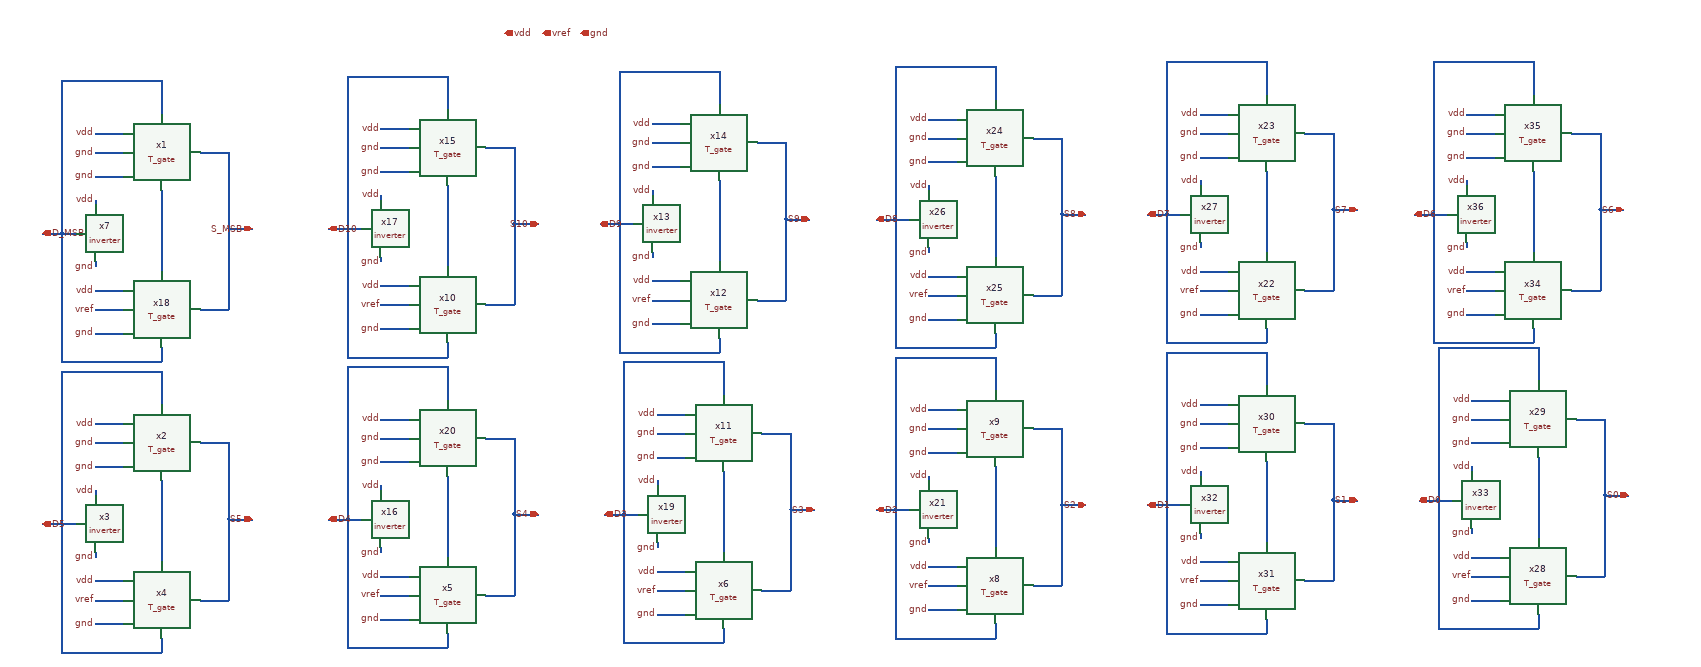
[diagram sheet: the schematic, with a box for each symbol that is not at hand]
v {xschem version=3.4.8RC file_version=1.3}
G {}
K {}
V {}
S {}
F {}
E {}
N 440 -690 440 -660 {lab=D_MSB}
N 520 -770 580 -770 {lab=S_MSB}
N 440 -1020 440 -850 {lab=#net1}
N 520 -1100 580 -1100 {lab=S_MSB}
N 580 -940 580 -770 {lab=S_MSB}
N 580 -1100 580 -940 {lab=S_MSB}
N 440 -1250 440 -1180 {lab=D_MSB}
N 230 -1250 440 -1250 {lab=D_MSB}
N 230 -1250 230 -930 {lab=D_MSB}
N 230 -930 260 -930 {lab=D_MSB}
N 300 -770 360 -770 {lab=vref}
N 300 -720 360 -720 {lab=gnd}
N 300 -810 360 -810 {lab=vdd}
N 230 -930 230 -660 {lab=D_MSB}
N 230 -660 440 -660 {lab=D_MSB}
N 300 -1100 360 -1100 {lab=gnd}
N 300 -1050 360 -1050 {lab=gnd}
N 300 -1140 360 -1140 {lab=vdd}
N 190 -930 230 -930 {lab=D_MSB}
N 300 -1000 300 -990 {lab=vdd}
N 300 -870 300 -860 {lab=gnd}
N 580 -940 630 -940 {lab=S_MSB}
N 1610 -710 1610 -680 {lab=D9}
N 1690 -790 1750 -790 {lab=S9}
N 1610 -1040 1610 -870 {lab=#net2}
N 1690 -1120 1750 -1120 {lab=S9}
N 1750 -960 1750 -790 {lab=S9}
N 1750 -1120 1750 -960 {lab=S9}
N 1610 -1270 1610 -1200 {lab=D9}
N 1400 -1270 1610 -1270 {lab=D9}
N 1400 -1270 1400 -950 {lab=D9}
N 1400 -950 1430 -950 {lab=D9}
N 1470 -790 1530 -790 {lab=vref}
N 1470 -740 1530 -740 {lab=gnd}
N 1470 -830 1530 -830 {lab=vdd}
N 1400 -950 1400 -680 {lab=D9}
N 1400 -680 1610 -680 {lab=D9}
N 1470 -1120 1530 -1120 {lab=gnd}
N 1470 -1070 1530 -1070 {lab=gnd}
N 1470 -1160 1530 -1160 {lab=vdd}
N 1360 -950 1400 -950 {lab=D9}
N 1470 -1020 1470 -1010 {lab=vdd}
N 1470 -890 1470 -880 {lab=gnd}
N 1750 -960 1800 -960 {lab=S9}
N 440 -80 440 -50 {lab=D5}
N 520 -160 580 -160 {lab=S5}
N 440 -410 440 -240 {lab=#net3}
N 520 -490 580 -490 {lab=S5}
N 580 -330 580 -160 {lab=S5}
N 580 -490 580 -330 {lab=S5}
N 440 -640 440 -570 {lab=D5}
N 230 -640 440 -640 {lab=D5}
N 230 -640 230 -320 {lab=D5}
N 230 -320 260 -320 {lab=D5}
N 300 -160 360 -160 {lab=vref}
N 300 -110 360 -110 {lab=gnd}
N 300 -200 360 -200 {lab=vdd}
N 230 -320 230 -50 {lab=D5}
N 230 -50 440 -50 {lab=D5}
N 300 -490 360 -490 {lab=gnd}
N 300 -440 360 -440 {lab=gnd}
N 300 -530 360 -530 {lab=vdd}
N 190 -320 230 -320 {lab=D5}
N 300 -390 300 -380 {lab=vdd}
N 300 -260 300 -250 {lab=gnd}
N 580 -330 630 -330 {lab=S5}
N 1040 -90 1040 -60 {lab=D4}
N 1120 -170 1180 -170 {lab=S4}
N 1040 -420 1040 -250 {lab=#net4}
N 1120 -500 1180 -500 {lab=S4}
N 1180 -340 1180 -170 {lab=S4}
N 1180 -500 1180 -340 {lab=S4}
N 1040 -650 1040 -580 {lab=D4}
N 830 -650 1040 -650 {lab=D4}
N 830 -650 830 -330 {lab=D4}
N 830 -330 860 -330 {lab=D4}
N 900 -170 960 -170 {lab=vref}
N 900 -120 960 -120 {lab=gnd}
N 900 -210 960 -210 {lab=vdd}
N 830 -330 830 -60 {lab=D4}
N 830 -60 1040 -60 {lab=D4}
N 900 -500 960 -500 {lab=gnd}
N 900 -450 960 -450 {lab=gnd}
N 900 -540 960 -540 {lab=vdd}
N 790 -330 830 -330 {lab=D4}
N 900 -400 900 -390 {lab=vdd}
N 900 -270 900 -260 {lab=gnd}
N 1180 -340 1230 -340 {lab=S4}
N 1620 -100 1620 -70 {lab=D3}
N 1700 -180 1760 -180 {lab=S3}
N 1620 -430 1620 -260 {lab=#net5}
N 1700 -510 1760 -510 {lab=S3}
N 1760 -350 1760 -180 {lab=S3}
N 1760 -510 1760 -350 {lab=S3}
N 1620 -660 1620 -590 {lab=D3}
N 1410 -660 1620 -660 {lab=D3}
N 1410 -660 1410 -340 {lab=D3}
N 1410 -340 1440 -340 {lab=D3}
N 1480 -180 1540 -180 {lab=vref}
N 1480 -130 1540 -130 {lab=gnd}
N 1480 -220 1540 -220 {lab=vdd}
N 1410 -340 1410 -70 {lab=D3}
N 1410 -70 1620 -70 {lab=D3}
N 1480 -510 1540 -510 {lab=gnd}
N 1480 -460 1540 -460 {lab=gnd}
N 1480 -550 1540 -550 {lab=vdd}
N 1370 -340 1410 -340 {lab=D3}
N 1480 -410 1480 -400 {lab=vdd}
N 1480 -280 1480 -270 {lab=gnd}
N 1760 -350 1810 -350 {lab=S3}
N 2190 -110 2190 -80 {lab=D2}
N 2270 -190 2330 -190 {lab=S2}
N 2190 -440 2190 -270 {lab=#net6}
N 2270 -520 2330 -520 {lab=S2}
N 2330 -360 2330 -190 {lab=S2}
N 2330 -520 2330 -360 {lab=S2}
N 2190 -670 2190 -600 {lab=D2}
N 1980 -670 2190 -670 {lab=D2}
N 1980 -670 1980 -350 {lab=D2}
N 1980 -350 2010 -350 {lab=D2}
N 2050 -190 2110 -190 {lab=vref}
N 2050 -140 2110 -140 {lab=gnd}
N 2050 -230 2110 -230 {lab=vdd}
N 1980 -350 1980 -80 {lab=D2}
N 1980 -80 2190 -80 {lab=D2}
N 2050 -520 2110 -520 {lab=gnd}
N 2050 -470 2110 -470 {lab=gnd}
N 2050 -560 2110 -560 {lab=vdd}
N 1940 -350 1980 -350 {lab=D2}
N 2050 -420 2050 -410 {lab=vdd}
N 2050 -290 2050 -280 {lab=gnd}
N 2330 -360 2380 -360 {lab=S2}
N 2190 -720 2190 -690 {lab=D8}
N 2270 -800 2330 -800 {lab=S8}
N 2190 -1050 2190 -880 {lab=#net7}
N 2270 -1130 2330 -1130 {lab=S8}
N 2330 -970 2330 -800 {lab=S8}
N 2330 -1130 2330 -970 {lab=S8}
N 2190 -1280 2190 -1210 {lab=D8}
N 1980 -1280 2190 -1280 {lab=D8}
N 1980 -1280 1980 -960 {lab=D8}
N 1980 -960 2010 -960 {lab=D8}
N 2050 -800 2110 -800 {lab=vref}
N 2050 -750 2110 -750 {lab=gnd}
N 2050 -840 2110 -840 {lab=vdd}
N 1980 -960 1980 -690 {lab=D8}
N 1980 -690 2190 -690 {lab=D8}
N 2050 -1130 2110 -1130 {lab=gnd}
N 2050 -1080 2110 -1080 {lab=gnd}
N 2050 -1170 2110 -1170 {lab=vdd}
N 1940 -960 1980 -960 {lab=D8}
N 2050 -1030 2050 -1020 {lab=vdd}
N 2050 -900 2050 -890 {lab=gnd}
N 2330 -970 2380 -970 {lab=S8}
N 2760 -730 2760 -700 {lab=D7}
N 2840 -810 2900 -810 {lab=S7}
N 2760 -1060 2760 -890 {lab=#net8}
N 2840 -1140 2900 -1140 {lab=S7}
N 2900 -980 2900 -810 {lab=S7}
N 2900 -1140 2900 -980 {lab=S7}
N 2760 -1290 2760 -1220 {lab=D7}
N 2550 -1290 2760 -1290 {lab=D7}
N 2550 -1290 2550 -970 {lab=D7}
N 2550 -970 2580 -970 {lab=D7}
N 2620 -810 2680 -810 {lab=vref}
N 2620 -760 2680 -760 {lab=gnd}
N 2620 -850 2680 -850 {lab=vdd}
N 2550 -970 2550 -700 {lab=D7}
N 2550 -700 2760 -700 {lab=D7}
N 2620 -1090 2680 -1090 {lab=gnd}
N 2620 -1180 2680 -1180 {lab=vdd}
N 2510 -970 2550 -970 {lab=D7}
N 2620 -1040 2620 -1030 {lab=vdd}
N 2620 -910 2620 -900 {lab=gnd}
N 2900 -980 2950 -980 {lab=S7}
N 2760 -120 2760 -90 {lab=D1}
N 2840 -200 2900 -200 {lab=S1}
N 2760 -450 2760 -280 {lab=#net9}
N 2840 -530 2900 -530 {lab=S1}
N 2900 -370 2900 -200 {lab=S1}
N 2900 -530 2900 -370 {lab=S1}
N 2760 -680 2760 -610 {lab=D1}
N 2550 -680 2760 -680 {lab=D1}
N 2550 -680 2550 -360 {lab=D1}
N 2550 -360 2580 -360 {lab=D1}
N 2620 -200 2680 -200 {lab=vref}
N 2620 -150 2680 -150 {lab=gnd}
N 2620 -240 2680 -240 {lab=vdd}
N 2550 -360 2550 -90 {lab=D1}
N 2550 -90 2760 -90 {lab=D1}
N 2620 -530 2680 -530 {lab=gnd}
N 2620 -480 2680 -480 {lab=gnd}
N 2620 -570 2680 -570 {lab=vdd}
N 2510 -360 2550 -360 {lab=D1}
N 2620 -430 2620 -420 {lab=vdd}
N 2620 -300 2620 -290 {lab=gnd}
N 2900 -370 2950 -370 {lab=S1}
N 3330 -130 3330 -100 {lab=D0}
N 3410 -210 3470 -210 {lab=S0}
N 3330 -460 3330 -290 {lab=#net10}
N 3410 -540 3470 -540 {lab=S0}
N 3470 -380 3470 -210 {lab=S0}
N 3470 -540 3470 -380 {lab=S0}
N 3330 -690 3330 -620 {lab=D0}
N 3120 -690 3330 -690 {lab=D0}
N 3120 -690 3120 -370 {lab=D0}
N 3120 -370 3150 -370 {lab=D0}
N 3190 -210 3250 -210 {lab=vref}
N 3190 -160 3250 -160 {lab=gnd}
N 3190 -250 3250 -250 {lab=vdd}
N 3120 -370 3120 -100 {lab=D0}
N 3120 -100 3330 -100 {lab=D0}
N 3190 -540 3250 -540 {lab=gnd}
N 3190 -490 3250 -490 {lab=gnd}
N 3190 -580 3250 -580 {lab=vdd}
N 3080 -370 3120 -370 {lab=D0}
N 3190 -440 3190 -430 {lab=vdd}
N 3190 -310 3190 -300 {lab=gnd}
N 3470 -380 3520 -380 {lab=S0}
N 3320 -730 3320 -700 {lab=D6}
N 3400 -810 3460 -810 {lab=S6}
N 3320 -1060 3320 -890 {lab=#net11}
N 3400 -1140 3460 -1140 {lab=S6}
N 3460 -980 3460 -810 {lab=S6}
N 3460 -1140 3460 -980 {lab=S6}
N 3320 -1290 3320 -1220 {lab=D6}
N 3110 -1290 3320 -1290 {lab=D6}
N 3110 -1290 3110 -970 {lab=D6}
N 3110 -970 3140 -970 {lab=D6}
N 3180 -810 3240 -810 {lab=vref}
N 3180 -760 3240 -760 {lab=gnd}
N 3180 -850 3240 -850 {lab=vdd}
N 3110 -970 3110 -700 {lab=D6}
N 3110 -700 3320 -700 {lab=D6}
N 3180 -1140 3240 -1140 {lab=gnd}
N 3180 -1090 3240 -1090 {lab=gnd}
N 3180 -1180 3240 -1180 {lab=vdd}
N 3070 -970 3110 -970 {lab=D6}
N 3180 -1040 3180 -1030 {lab=vdd}
N 3180 -910 3180 -900 {lab=gnd}
N 3460 -980 3510 -980 {lab=S6}
N 1040 -700 1040 -670 {lab=D10}
N 1120 -780 1180 -780 {lab=S10}
N 1040 -1030 1040 -860 {lab=#net12}
N 1120 -1110 1180 -1110 {lab=S10}
N 1180 -950 1180 -780 {lab=S10}
N 1180 -1110 1180 -950 {lab=S10}
N 1040 -1260 1040 -1190 {lab=D10}
N 830 -1260 1040 -1260 {lab=D10}
N 830 -1260 830 -940 {lab=D10}
N 830 -940 860 -940 {lab=D10}
N 900 -780 960 -780 {lab=vref}
N 900 -730 960 -730 {lab=gnd}
N 900 -820 960 -820 {lab=vdd}
N 830 -940 830 -670 {lab=D10}
N 830 -670 1040 -670 {lab=D10}
N 900 -1110 960 -1110 {lab=gnd}
N 900 -1060 960 -1060 {lab=gnd}
N 900 -1150 960 -1150 {lab=vdd}
N 790 -940 830 -940 {lab=D10}
N 900 -1010 900 -1000 {lab=vdd}
N 900 -880 900 -870 {lab=gnd}
N 1180 -950 1230 -950 {lab=S10}
N 2620 -1140 2680 -1140 {lab=gnd}
C {iopin.sym} 630 -940 0 0 {name=p5 lab=S_MSB}
C {lab_pin.sym} 300 -810 0 0 {name=p6 sig_type=std_logic lab=vdd}
C {lab_pin.sym} 300 -1140 0 0 {name=p7 sig_type=std_logic lab=vdd}
C {lab_pin.sym} 300 -1100 0 0 {name=p8 sig_type=std_logic lab=gnd}
C {lab_pin.sym} 300 -1000 0 0 {name=p4 sig_type=std_logic lab=vdd}
C {iopin.sym} 190 -930 0 1 {name=p19 lab=D_MSB}
C {iopin.sym} 1800 -960 0 0 {name=p17 lab=S9}
C {lab_pin.sym} 1470 -830 0 0 {name=p20 sig_type=std_logic lab=vdd}
C {lab_pin.sym} 1470 -1160 0 0 {name=p21 sig_type=std_logic lab=vdd}
C {lab_pin.sym} 1470 -1120 0 0 {name=p22 sig_type=std_logic lab=gnd}
C {lab_pin.sym} 1470 -1020 0 0 {name=p23 sig_type=std_logic lab=vdd}
C {iopin.sym} 1360 -950 0 1 {name=p24 lab=D9}
C {iopin.sym} 630 -330 0 0 {name=p25 lab=S5}
C {lab_pin.sym} 300 -200 0 0 {name=p26 sig_type=std_logic lab=vdd}
C {lab_pin.sym} 300 -530 0 0 {name=p27 sig_type=std_logic lab=vdd}
C {lab_pin.sym} 300 -490 0 0 {name=p28 sig_type=std_logic lab=gnd}
C {lab_pin.sym} 300 -390 0 0 {name=p29 sig_type=std_logic lab=vdd}
C {iopin.sym} 1230 -340 0 0 {name=p30 lab=S4}
C {lab_pin.sym} 900 -210 0 0 {name=p31 sig_type=std_logic lab=vdd}
C {lab_pin.sym} 900 -540 0 0 {name=p32 sig_type=std_logic lab=vdd}
C {lab_pin.sym} 900 -500 0 0 {name=p33 sig_type=std_logic lab=gnd}
C {lab_pin.sym} 900 -400 0 0 {name=p34 sig_type=std_logic lab=vdd}
C {iopin.sym} 1810 -350 0 0 {name=p35 lab=S3}
C {lab_pin.sym} 1480 -220 0 0 {name=p36 sig_type=std_logic lab=vdd}
C {lab_pin.sym} 1480 -550 0 0 {name=p37 sig_type=std_logic lab=vdd}
C {lab_pin.sym} 1480 -510 0 0 {name=p38 sig_type=std_logic lab=gnd}
C {lab_pin.sym} 1480 -410 0 0 {name=p39 sig_type=std_logic lab=vdd}
C {iopin.sym} 190 -320 0 1 {name=p40 lab=D5}
C {iopin.sym} 790 -330 0 1 {name=p41 lab=D4}
C {iopin.sym} 1370 -340 0 1 {name=p42 lab=D3}
C {iopin.sym} 2380 -360 0 0 {name=p43 lab=S2}
C {lab_pin.sym} 2050 -230 0 0 {name=p44 sig_type=std_logic lab=vdd}
C {lab_pin.sym} 2050 -560 0 0 {name=p45 sig_type=std_logic lab=vdd}
C {lab_pin.sym} 2050 -520 0 0 {name=p46 sig_type=std_logic lab=gnd}
C {lab_pin.sym} 2050 -420 0 0 {name=p47 sig_type=std_logic lab=vdd}
C {iopin.sym} 1940 -350 0 1 {name=p48 lab=D2}
C {iopin.sym} 1160 -1350 0 1 {name=p49 lab=vdd}
C {iopin.sym} 1240 -1350 0 1 {name=p50 lab=vref}
C {iopin.sym} 1320 -1350 0 1 {name=p51 lab=gnd}
C {lab_pin.sym} 300 -1050 0 0 {name=p52 sig_type=std_logic lab=gnd}
C {lab_pin.sym} 300 -860 0 0 {name=p53 sig_type=std_logic lab=gnd}
C {lab_pin.sym} 300 -770 0 0 {name=p54 sig_type=std_logic lab=vref}
C {lab_pin.sym} 300 -720 0 0 {name=p55 sig_type=std_logic lab=gnd}
C {lab_pin.sym} 1470 -1070 0 0 {name=p65 sig_type=std_logic lab=gnd}
C {lab_pin.sym} 1470 -880 0 0 {name=p66 sig_type=std_logic lab=gnd}
C {lab_pin.sym} 1470 -790 0 0 {name=p67 sig_type=std_logic lab=vref}
C {lab_pin.sym} 1470 -740 0 0 {name=p68 sig_type=std_logic lab=gnd}
C {lab_pin.sym} 300 -440 0 0 {name=p69 sig_type=std_logic lab=gnd}
C {lab_pin.sym} 300 -250 0 0 {name=p70 sig_type=std_logic lab=gnd}
C {lab_pin.sym} 300 -160 0 0 {name=p71 sig_type=std_logic lab=vref}
C {lab_pin.sym} 300 -110 0 0 {name=p72 sig_type=std_logic lab=gnd}
C {lab_pin.sym} 900 -450 0 0 {name=p73 sig_type=std_logic lab=gnd}
C {lab_pin.sym} 900 -260 0 0 {name=p74 sig_type=std_logic lab=gnd}
C {lab_pin.sym} 900 -170 0 0 {name=p75 sig_type=std_logic lab=vref}
C {lab_pin.sym} 900 -120 0 0 {name=p76 sig_type=std_logic lab=gnd}
C {lab_pin.sym} 1480 -460 0 0 {name=p77 sig_type=std_logic lab=gnd}
C {lab_pin.sym} 1480 -180 0 0 {name=p78 sig_type=std_logic lab=vref}
C {lab_pin.sym} 1480 -130 0 0 {name=p79 sig_type=std_logic lab=gnd}
C {lab_pin.sym} 1480 -270 0 0 {name=p80 sig_type=std_logic lab=gnd}
C {lab_pin.sym} 2050 -470 0 0 {name=p81 sig_type=std_logic lab=gnd}
C {lab_pin.sym} 2050 -280 0 0 {name=p82 sig_type=std_logic lab=gnd}
C {lab_pin.sym} 2050 -190 0 0 {name=p83 sig_type=std_logic lab=vref}
C {lab_pin.sym} 2050 -140 0 0 {name=p84 sig_type=std_logic lab=gnd}
C {T_gate.sym} 440 -1100 0 0 {name=x1}
C {T_gate.sym} 440 -490 0 0 {name=x2}
C {T_gate.sym} 440 -160 0 0 {name=x4}
C {T_gate.sym} 1040 -170 0 0 {name=x5}
C {T_gate.sym} 1620 -180 0 0 {name=x6}
C {T_gate.sym} 2190 -190 0 0 {name=x8}
C {T_gate.sym} 2190 -520 0 0 {name=x9}
C {T_gate.sym} 1620 -510 0 0 {name=x11}
C {T_gate.sym} 1610 -790 0 0 {name=x12}
C {T_gate.sym} 1610 -1120 0 0 {name=x14}
C {T_gate.sym} 440 -770 0 0 {name=x18}
C {T_gate.sym} 1040 -500 0 0 {name=x20}
C {inverter.sym} 280 -320 0 0 {name=x3}
C {inverter.sym} 280 -930 0 0 {name=x7}
C {inverter.sym} 1450 -950 0 0 {name=x13}
C {inverter.sym} 880 -330 0 0 {name=x16}
C {inverter.sym} 1460 -340 0 0 {name=x19}
C {inverter.sym} 2030 -350 0 0 {name=x21}
C {iopin.sym} 2380 -970 0 0 {name=p1 lab=S8}
C {lab_pin.sym} 2050 -840 0 0 {name=p2 sig_type=std_logic lab=vdd}
C {lab_pin.sym} 2050 -1170 0 0 {name=p3 sig_type=std_logic lab=vdd}
C {lab_pin.sym} 2050 -1130 0 0 {name=p9 sig_type=std_logic lab=gnd}
C {lab_pin.sym} 2050 -1030 0 0 {name=p10 sig_type=std_logic lab=vdd}
C {iopin.sym} 1940 -960 0 1 {name=p12 lab=D8}
C {iopin.sym} 2950 -980 0 0 {name=p56 lab=S7}
C {lab_pin.sym} 2620 -850 0 0 {name=p57 sig_type=std_logic lab=vdd}
C {lab_pin.sym} 2620 -1180 0 0 {name=p58 sig_type=std_logic lab=vdd}
C {lab_pin.sym} 2620 -1140 0 0 {name=p59 sig_type=std_logic lab=gnd}
C {lab_pin.sym} 2620 -1040 0 0 {name=p60 sig_type=std_logic lab=vdd}
C {iopin.sym} 2510 -970 0 1 {name=p85 lab=D7}
C {lab_pin.sym} 2050 -1080 0 0 {name=p86 sig_type=std_logic lab=gnd}
C {lab_pin.sym} 2050 -890 0 0 {name=p87 sig_type=std_logic lab=gnd}
C {lab_pin.sym} 2050 -800 0 0 {name=p88 sig_type=std_logic lab=vref}
C {lab_pin.sym} 2050 -750 0 0 {name=p89 sig_type=std_logic lab=gnd}
C {lab_pin.sym} 2620 -1090 0 0 {name=p90 sig_type=std_logic lab=gnd}
C {lab_pin.sym} 2620 -900 0 0 {name=p91 sig_type=std_logic lab=gnd}
C {lab_pin.sym} 2620 -810 0 0 {name=p92 sig_type=std_logic lab=vref}
C {lab_pin.sym} 2620 -760 0 0 {name=p93 sig_type=std_logic lab=gnd}
C {T_gate.sym} 2760 -810 0 0 {name=x22}
C {T_gate.sym} 2760 -1140 0 0 {name=x23}
C {T_gate.sym} 2190 -1130 0 0 {name=x24}
C {T_gate.sym} 2190 -800 0 0 {name=x25}
C {inverter.sym} 2030 -960 0 0 {name=x26}
C {inverter.sym} 2600 -970 0 0 {name=x27}
C {iopin.sym} 2950 -370 0 0 {name=p94 lab=S1}
C {lab_pin.sym} 2620 -240 0 0 {name=p95 sig_type=std_logic lab=vdd}
C {lab_pin.sym} 2620 -570 0 0 {name=p96 sig_type=std_logic lab=vdd}
C {lab_pin.sym} 2620 -530 0 0 {name=p97 sig_type=std_logic lab=gnd}
C {lab_pin.sym} 2620 -430 0 0 {name=p98 sig_type=std_logic lab=vdd}
C {iopin.sym} 2510 -360 0 1 {name=p99 lab=D1}
C {iopin.sym} 3520 -380 0 0 {name=p100 lab=S0}
C {lab_pin.sym} 3190 -250 0 0 {name=p101 sig_type=std_logic lab=vdd}
C {lab_pin.sym} 3190 -580 0 0 {name=p102 sig_type=std_logic lab=vdd}
C {lab_pin.sym} 3190 -540 0 0 {name=p103 sig_type=std_logic lab=gnd}
C {lab_pin.sym} 3190 -440 0 0 {name=p104 sig_type=std_logic lab=vdd}
C {iopin.sym} 3080 -370 0 1 {name=p105 lab=D0}
C {lab_pin.sym} 2620 -480 0 0 {name=p106 sig_type=std_logic lab=gnd}
C {lab_pin.sym} 2620 -290 0 0 {name=p107 sig_type=std_logic lab=gnd}
C {lab_pin.sym} 2620 -200 0 0 {name=p108 sig_type=std_logic lab=vref}
C {lab_pin.sym} 2620 -150 0 0 {name=p109 sig_type=std_logic lab=gnd}
C {lab_pin.sym} 3190 -490 0 0 {name=p110 sig_type=std_logic lab=gnd}
C {lab_pin.sym} 3190 -300 0 0 {name=p111 sig_type=std_logic lab=gnd}
C {lab_pin.sym} 3190 -210 0 0 {name=p112 sig_type=std_logic lab=vref}
C {lab_pin.sym} 3190 -160 0 0 {name=p113 sig_type=std_logic lab=gnd}
C {T_gate.sym} 3330 -210 0 0 {name=x28}
C {T_gate.sym} 3330 -540 0 0 {name=x29}
C {T_gate.sym} 2760 -530 0 0 {name=x30}
C {T_gate.sym} 2760 -200 0 0 {name=x31}
C {inverter.sym} 2600 -360 0 0 {name=x32}
C {inverter.sym} 3170 -370 0 0 {name=x33}
C {iopin.sym} 3510 -980 0 0 {name=p114 lab=S6}
C {lab_pin.sym} 3180 -850 0 0 {name=p115 sig_type=std_logic lab=vdd}
C {lab_pin.sym} 3180 -1180 0 0 {name=p116 sig_type=std_logic lab=vdd}
C {lab_pin.sym} 3180 -1140 0 0 {name=p117 sig_type=std_logic lab=gnd}
C {lab_pin.sym} 3180 -1040 0 0 {name=p118 sig_type=std_logic lab=vdd}
C {iopin.sym} 3070 -970 0 1 {name=p119 lab=D6}
C {lab_pin.sym} 3180 -1090 0 0 {name=p120 sig_type=std_logic lab=gnd}
C {lab_pin.sym} 3180 -900 0 0 {name=p121 sig_type=std_logic lab=gnd}
C {lab_pin.sym} 3180 -810 0 0 {name=p122 sig_type=std_logic lab=vref}
C {lab_pin.sym} 3180 -760 0 0 {name=p123 sig_type=std_logic lab=gnd}
C {T_gate.sym} 3320 -810 0 0 {name=x34}
C {T_gate.sym} 3320 -1140 0 0 {name=x35}
C {inverter.sym} 3160 -970 0 0 {name=x36}
C {iopin.sym} 1230 -950 0 0 {name=p11 lab=S10}
C {lab_pin.sym} 900 -820 0 0 {name=p13 sig_type=std_logic lab=vdd}
C {lab_pin.sym} 900 -1150 0 0 {name=p14 sig_type=std_logic lab=vdd}
C {lab_pin.sym} 900 -1110 0 0 {name=p15 sig_type=std_logic lab=gnd}
C {lab_pin.sym} 900 -1010 0 0 {name=p16 sig_type=std_logic lab=vdd}
C {iopin.sym} 790 -940 0 1 {name=p18 lab=D10}
C {lab_pin.sym} 900 -1060 0 0 {name=p61 sig_type=std_logic lab=gnd}
C {lab_pin.sym} 900 -870 0 0 {name=p62 sig_type=std_logic lab=gnd}
C {lab_pin.sym} 900 -780 0 0 {name=p63 sig_type=std_logic lab=vref}
C {lab_pin.sym} 900 -730 0 0 {name=p64 sig_type=std_logic lab=gnd}
C {T_gate.sym} 1040 -780 0 0 {name=x10}
C {T_gate.sym} 1040 -1110 0 0 {name=x15}
C {inverter.sym} 880 -940 0 0 {name=x17}
